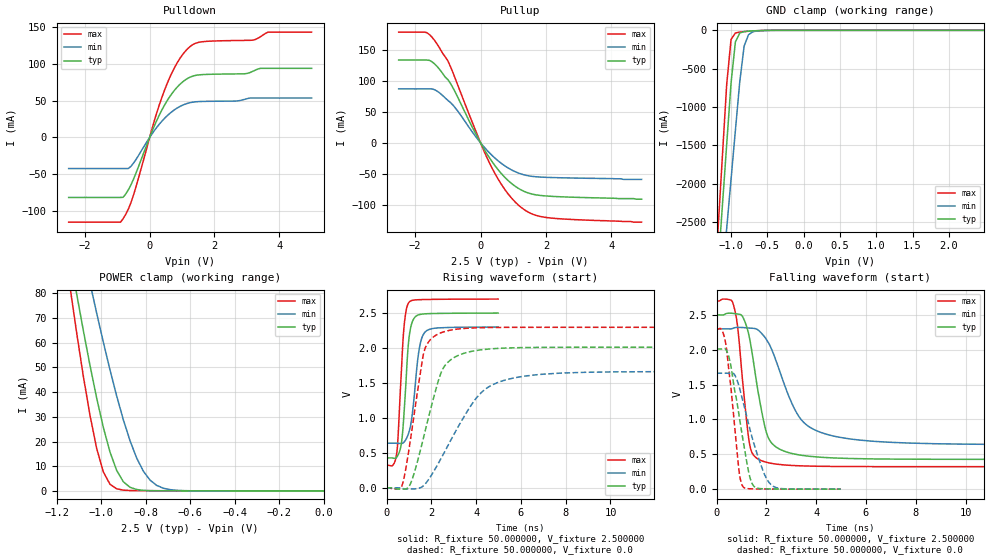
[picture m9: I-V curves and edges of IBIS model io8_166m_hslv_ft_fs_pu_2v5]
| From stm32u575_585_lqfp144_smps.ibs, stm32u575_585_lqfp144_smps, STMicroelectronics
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|   Model io8_166m_hslv_ft_fs_pu_2v5
[Model]  io8_166m_hslv_ft_fs_pu_2v5
Model_type I/O
Polarity   Non-Inverting
Enable   Active-Low
Vinl =   0.750000V
Vinh =   1.750000V
Vmeas =  1.250000V
Cref =   50.000000pF
Rref =   100.000000M
Vref =   0.0V
C_comp   3.458600pF   3.458000pF   3.495600pF
[Temperature Range]   25.000000   0.140000k   -40.000000
[Pullup Reference]   2.500000V   2.300000V   2.700000V
[Pulldown Reference]   0.0V   0.0V   0.0V
[POWER Clamp Reference]   2.500000V   2.300000V   2.700000V
[GND Clamp Reference]   0.0V   0.0V   0.0V
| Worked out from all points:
|   slope of the pulldown table from 0 to 0.375 V, typ, clamps not added: 10.1 ohm
|   slope of the pullup table from 0 to 0.375 V, typ, clamps not added: 11.7 ohm
|   GND clamp passes 1 mA (typ) near -0.50 V on its own axis
|   POWER clamp passes 1 mA (typ) near -0.85 V on its own axis
|   rising waveform, R_fixture 50.000000, V_fixture 2.500000: 20-80 % time 254ps typ, 336ps min, 234ps max; typ from 0.428 V to 2.5 V
|   rising waveform, R_fixture 50.000000, V_fixture 0.0: 20-80 % time 989ps typ, 1.85ns min, 647ps max; typ from 0 V to 2.01 V
|   falling waveform, R_fixture 50.000000, V_fixture 2.500000: 20-80 % time 613ps typ, 1.21ns min, 386ps max; typ from 2.5 V to 0.428 V
|   falling waveform, R_fixture 50.000000, V_fixture 0.0: 20-80 % time 563ps typ, 788ps min, 390ps max; typ from 2.01 V to 0 V
[Pulldown]
|Voltage   I(typ)   I(min)   I(max)
-2.5V     -81.62mA   -42.31mA   -115.3mA
-900mV    -81.62mA   -42.31mA   -115.3mA
-820mV    -81.43mA   -42.31mA   -110.6mA
-500mV    -56.95mA   -35.08mA   -78.57mA
140mV     15.18mA    9.02mA     22.02mA
460mV     44mA       25.98mA    64.38mA
860mV     68.91mA    40.27mA    102.2mA
1.26V     82.21mA    47.42mA    124mA
1.66V     85.54mA    49mA       130.3mA
3.18V     89.84mA    53.62mA    132.3mA
3.66V     93.97mA    53.62mA    143.3mA
5V        93.97mA    53.62mA    143.3mA
[Pullup]
|Voltage   I(typ)   I(min)   I(max)
-2.5V     133.3mA    86.84mA    178.4mA
-1.64V    133.3mA    86.84mA    177.4mA
-1.4V     127mA      85.44mA    164.7mA
-1V       102mA      68.42mA    132.3mA
-920mV    95.86mA    64.93mA    123mA
-120mV    11.81mA    8.046mA    15.6mA
360mV     -30.97mA   -20.78mA   -41.56mA
760mV     -56.64mA   -37.85mA   -76.55mA
1.24V     -75.99mA   -50.28mA   -104.1mA
1.64V     -83.42mA   -54.54mA   -116.1mA
2.04V     -85.88mA   -55.77mA   -120.6mA
4.92V     -91mA      -59mA      -128mA
[GND_clamp]
|Voltage   I(typ)   I(min)   I(max)
-2.5V     -9.641A    -9.693A    -9.352A
-1.18V    -3.114A    -3.874A    -2.614A
-1.12V    -2.301A    -3.23A     -1.656A
-1.06V    -1.489A    -2.587A    -706.2mA
-1V       -685.8mA   -1.945A    -119.3mA
-940mV    -149.7mA   -1.304A    -34.73mA
-880mV    -35.54mA   -672.6mA   -23.06mA
-820mV    -16.2mA    -206.4mA   -17.27mA
-760mV    -10.58mA   -57.55mA   -12.41mA
-700mV    -7.152mA   -18.74mA   -8.24mA
-400mV    -103.3uA   -378.6uA   -41.75uA
2.48V     0A         13.22nA    0A
[POWER_clamp]
|Voltage   I(typ)   I(min)   I(max)
-2.49V    881.1mA    773.1mA    1.07A
-1.14V    95.32mA    122.8mA    82.93mA
-1.11V    79.97mA    109.7mA    64.26mA
-1.05V    50.95mA    84.3mA     30.69mA
-1.02V    37.7mA     72.08mA    17.29mA
-990mV    25.79mA    60.29mA    7.738mA
-930mV    8.312mA    38.47mA    853.1uA
-900mV    3.712mA    28.81mA    313.6uA
-840mV    566.2uA    13.29mA    123.7uA
-780mV    119uA      4.365mA    94.04uA
-660mV    38.98uA    251.5uA    57.76uA
0V        0A         18.93nA    0A
[Ramp]
| variable   typ   min   max
dV/dt_r  1.20644/0.98793n   0.99759/1.84670n   1.37763/0.64625n
dV/dt_f  1.24313/0.61101n   0.99709/1.20941n   1.42607/0.38514n
R_load = 50.000000
[Rising Waveform]
R_fixture= 50.000000
V_fixture= 2.500000
V_fixture_min= 2.300000
V_fixture_max= 2.700000
|time   V(typ)   V(min)   V(max)
0s        428.1mV    638.1mV    323.2mV
450.5ps   437.8mV    638.2mV    480.5mV
520.5ps   472.8mV    637.4mV    762.2mV
640.6ps   593.6mV    633.9mV    1.536V
790.8ps   1.113V     657.6mV    2.332V
991ps     2.106V     785.8mV    2.649V
1.151ns   2.374V     1.057V     2.682V
1.451ns   2.476V     1.969V     2.691V
1.722ns   2.489V     2.229V     2.694V
4.985ns   2.5V       2.3V       2.7V
[Rising Waveform]
R_fixture= 50.000000
V_fixture= 0.0
V_fixture_min= 0.0
V_fixture_max= 0.0
|time   V(typ)   V(min)   V(max)
0s        416.1uV    544uV      450.3uV
680.7ps   -18.71mV   -6.469mV   22.94mV
1.041ns   40.25mV    -16.39mV   630.8mV
1.682ns   757.1mV    40.34mV    1.956V
1.962ns   1.117V     159.6mV    2.121V
2.442ns   1.653V     425.9mV    2.219V
3.003ns   1.861V     760.8mV    2.264V
4.124ns   1.97V      1.328V     2.29V
5.686ns   2.003V     1.572V     2.296V
19.94ns   2.011V     1.663V     2.296V
[Falling Waveform]
R_fixture= 50.000000
V_fixture= 2.500000
V_fixture_min= 2.300000
V_fixture_max= 2.700000
|time   V(typ)   V(min)   V(max)
0s        2.5V       2.3V       2.7V
680.7ps   2.521V     2.31V      2.644V
840.8ps   2.513V     2.321V     2.35V
1.081ns   2.451V     2.318V     1.429V
1.361ns   2.099V     2.31V      589.5mV
1.882ns   993.4mV    2.206V     399mV
2.242ns   650.6mV    1.982V     367.9mV
3.323ns   491.4mV    1.034V     335.9mV
4.645ns   449.3mV    766.6mV    326.6mV
19.94ns   428.1mV    638.1mV    323.2mV
[Falling Waveform]
R_fixture= 50.000000
V_fixture= 0.0
V_fixture_min= 0.0
V_fixture_max= 0.0
|time   V(typ)   V(min)   V(max)
0s        2.011V     1.663V     2.296V
200.2ps   2.011V     1.663V     2.292V
370.4ps   2.005V     1.663V     2.086V
560.6ps   1.798V     1.666V     1.511V
900.9ps   1.068V     1.479V     271.9mV
1.071ns   688.2mV    1.244V     32.46mV
1.441ns   72.86mV    726.1mV    4.74mV
1.882ns   5.965mV    251.9mV    2.556mV
2.182ns   3.573mV    67.3mV     2.022mV
4.985ns   416.1uV    544uV      450.3uV
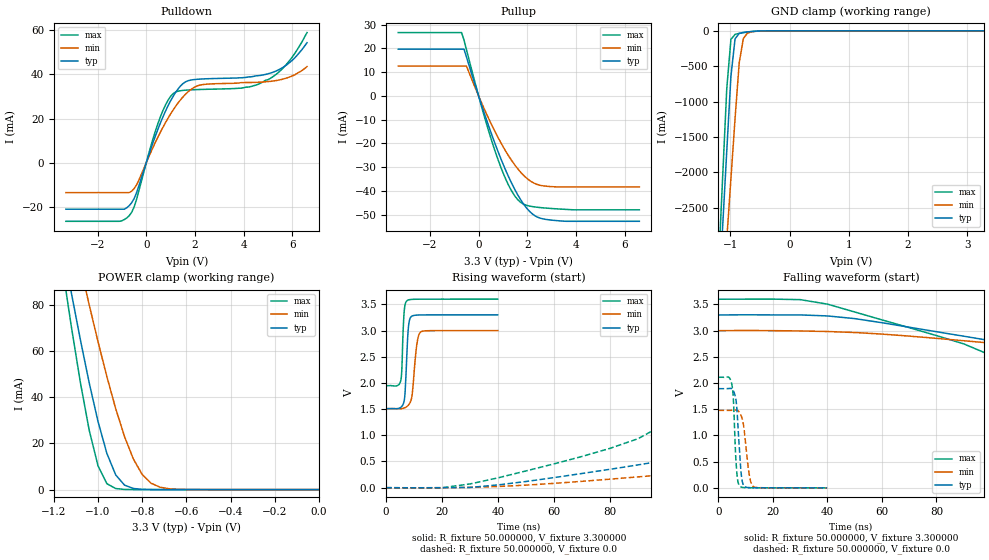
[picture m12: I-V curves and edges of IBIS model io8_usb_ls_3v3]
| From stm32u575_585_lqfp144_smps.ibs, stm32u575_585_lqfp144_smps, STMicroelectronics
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|   Model io8_usb_ls_3v3
[Model]  io8_usb_ls_3v3
Model_type I/O
Polarity   Non-Inverting
Enable   Active-Low
Vinl =   0.990000V
Vinh =   2.310000V
Vmeas =  1.650000V
Cref =   50.000000pF
Rref =   100.000000M
Vref =   0.0V
C_comp   7.156600pF   7.055100pF   7.302500pF
[Temperature Range]   25.000000   0.140000k   -40.000000
[Pullup Reference]   3.300000V   3.000000V   3.600000V
[Pulldown Reference]   0.0V   0.0V   0.0V
[POWER Clamp Reference]   3.300000V   3.000000V   3.600000V
[GND Clamp Reference]   0.0V   0.0V   0.0V
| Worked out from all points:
|   slope of the pulldown table from 0 to 0.495 V, typ, clamps not added: 31.7 ohm
|   slope of the pullup table from 0 to 0.495 V, typ, clamps not added: 32.8 ohm
|   GND clamp passes 1 mA (typ) near -0.45 V on its own axis
|   POWER clamp passes 1 mA (typ) near -0.85 V on its own axis
|   rising waveform, R_fixture 50.000000, V_fixture 3.300000: 20-80 % time 969ps typ, 1.53ns min, 711ps max; typ from 1.51 V to 3.3 V
|   rising waveform, R_fixture 50.000000, V_fixture 0.0: 20-80 % time 81.8ns typ, 127ns min, 54.5ns max; typ from 0 V to 1.89 V
|   falling waveform, R_fixture 50.000000, V_fixture 3.300000: 20-80 % time 79.6ns typ, 126ns min, 51ns max; typ from 3.3 V to 1.51 V
|   falling waveform, R_fixture 50.000000, V_fixture 0.0: 20-80 % time 1.41ns typ, 1.94ns min, 1.08ns max; typ from 1.89 V to 0 V
[Pulldown]
|Voltage   I(typ)   I(min)   I(max)
-3.3V     -21.02mA   -13.49mA   -26.5mA
-1.1V     -21.02mA   -13.49mA   -26.5mA
-700mV    -19.43mA   -13.49mA   -23.96mA
-500mV    -16.24mA   -11.71mA   -20.08mA
300mV     9.818mA    7.473mA    11.7mA
700mV     21.14mA    16.35mA    24.01mA
1.1V      30mA       23.83mA    31.23mA
1.6V      36.53mA    30.86mA    32.82mA
2.3V      37.91mA    35.33mA    33.18mA
5V        40.25mA    36.71mA    37.59mA
5.8V      44.59mA    38.47mA    45.12mA
6.6V      54.3mA     43.5mA     58.9mA
[Pullup]
|Voltage   I(typ)   I(min)   I(max)
-3.3V     19.68mA    12.58mA    26.67mA
-700mV    19.68mA    12.58mA    26.67mA
-600mV    19.68mA    12.58mA    23.57mA
-500mV    16.44mA    12.58mA    19.55mA
200mV     -6.28mA    -4.745mA   -7.389mA
700mV     -20.83mA   -15.6mA    -23.99mA
1.2V      -33.39mA   -24.77mA   -37mA
1.5V      -39.71mA   -29.31mA   -42.37mA
1.7V      -43.32mA   -31.86mA   -44.65mA
2.2V      -49.68mA   -36.36mA   -46.64mA
2.7V      -51.94mA   -37.98mA   -47.23mA
6.6V      -52.85mA   -38.36mA   -48.01mA
[GND_clamp]
|Voltage   I(typ)   I(min)   I(max)
-3.3V     -9.287A    -9.833A    -9.745A
-1.2V     -3.857A    -4.664A    -3.345A
-1.13V    -2.774A    -3.805A    -2.072A
-1.06V    -1.695A    -2.947A    -813.1mA
-990mV    -641.8mA   -2.091A    -120.9mA
-920mV    -113.3mA   -1.238A    -49.89mA
-850mV    -36.8mA    -452mA     -36.31mA
-780mV    -22.65mA   -108.9mA   -26.22mA
-710mV    -15.23mA   -32.27mA   -17.43mA
-570mV    -5.119mA   -7.032mA   -4.907mA
-360mV    -90.45uA   -461.6uA   -25.95uA
3.28V     0A         40.32nA    -16.18nA
[POWER_clamp]
|Voltage   I(typ)   I(min)   I(max)
-3.28V    1.355A     1.167A     1.664A
-1.16V    105.7mA    131.6mA    95.69mA
-1.12V    84.97mA    114mA      70.27mA
-1.08V    65.05mA    96.83mA    46.54mA
-1.04V    46.34mA    80.15mA    25.76mA
-1V       29.51mA    64.13mA    10.3mA
-960mV    15.69mA    48.99mA    2.571mA
-920mV    6.373mA    35.1mA     455.6uA
-840mV    490.7uA    13.24mA    11.36uA
-760mV    27.33uA    2.767mA    754.7nA
-640mV    348.1nA    134.1uA    754.7nA
0V        0A         50.53nA    0A
[Ramp]
| variable   typ   min   max
dV/dt_r  1.13586/81.45159n   0.88764/0.12625u   1.26642/54.16813n
dV/dt_f  1.07448/79.20631n   0.89406/0.12539u   0.99132/51.02099n
R_load = 50.000000
[Rising Waveform]
R_fixture= 50.000000
V_fixture= 3.300000
V_fixture_min= 3.000000
V_fixture_max= 3.600000
|time   V(typ)   V(min)   V(max)
0s        1.509V     1.51V      1.948V
5.205ns   1.533V     1.508V     2.042V
5.606ns   1.553V     1.509V     2.268V
6.326ns   1.634V     1.52V      3.272V
6.807ns   1.862V     1.53V      3.503V
7.928ns   3.043V     1.574V     3.584V
9.049ns   3.27V      1.7V       3.594V
10.97ns   3.295V     2.736V     3.598V
12.25ns   3.298V     2.967V     3.599V
39.88ns   3.3V       3V         3.6V
[Rising Waveform]
R_fixture= 50.000000
V_fixture= 0.0
V_fixture_min= 0.0
V_fixture_max= 0.0
|time   V(typ)   V(min)   V(max)
0s        53.51nV    540.9nV    167.4nV
30.03ns   4.933mV    5.77mV     71.95mV
70.07ns   271.8mV    121.6mV    597.4mV
90.09ns   435.6mV    206.3mV    936.6mV
110.1ns   617.8mV    299.3mV    1.63V
130.1ns   837.7mV    398.7mV    2.06V
170.2ns   1.604V     617.6mV    2.217V
260.3ns   1.915V     1.326V     2.216V
370.4ns   1.916V     1.458V     2.204V
4.985us   1.893V     1.479V     2.111V
[Falling Waveform]
R_fixture= 50.000000
V_fixture= 3.300000
V_fixture_min= 3.000000
V_fixture_max= 3.600000
|time   V(typ)   V(min)   V(max)
0s        3.3V       3V         3.6V
40.04ns   3.281V     2.984V     3.506V
90.09ns   2.894V     2.808V     2.747V
120.1ns   2.619V     2.667V     1.915V
140.1ns   2.372V     2.566V     1.772V
170.2ns   1.747V     2.4V       1.783V
200.2ns   1.537V     2.17V      1.807V
270.3ns   1.492V     1.658V     1.849V
400.4ns   1.498V     1.52V      1.895V
4.985us   1.509V     1.51V      1.948V
[Falling Waveform]
R_fixture= 50.000000
V_fixture= 0.0
V_fixture_min= 0.0
V_fixture_max= 0.0
|time   V(typ)   V(min)   V(max)
0s        1.893V     1.479V     2.111V
4.885ns   1.892V     1.48V      1.979V
5.445ns   1.852V     1.484V     1.706V
6.727ns   1.524V     1.486V     292mV
7.768ns   675.7mV    1.433V     35.28mV
8.408ns   236.6mV    1.365V     14.17mV
9.129ns   55.78mV    1.217V     6.831mV
11.21ns   4.765mV    278.2mV    2.764mV
12.57ns   2.651mV    33.78mV    1.939mV
39.88ns   53.51nV    540.9nV    167.4nV
